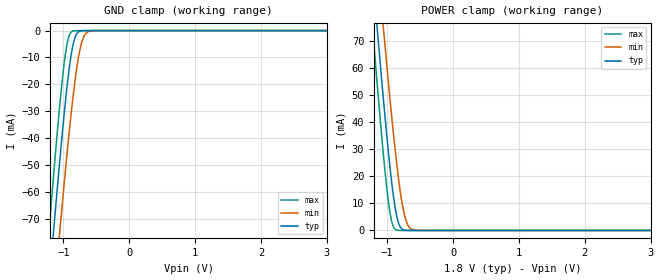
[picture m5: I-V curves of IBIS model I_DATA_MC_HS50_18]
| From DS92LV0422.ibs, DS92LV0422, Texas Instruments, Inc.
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|   I_DATA_MC_HS50_18
[Model]   I_DATA_MC_HS50_18
Model_type   Input
Vinl = 0.63V
Vinh = 1.17V
|   typ   min   max
|   (nom)   (weak)   (fast)
C_comp   0.5928pF   0.5928pF   0.5928pF
[Voltage Range]   1.800V   1.710V   1.890V
[Temperature Range]   25.0   105.0   -40.0
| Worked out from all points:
|   GND clamp passes 1 mA (typ) near -0.79 V on its own axis
|   POWER clamp passes 1 mA (typ) near -0.79 V on its own axis
[GND Clamp]
|   Voltage   I(typ)   I(min)   I(max)
-1.8V     -271mA     -291mA     -255.6mA
-1.228V   -97.13mA   -122.7mA   -76.8mA
-1.201V   -89.24mA   -115mA     -68.74mA
-1.147V   -73.66mA   -99.76mA   -52.9mA
-1.055V   -48.09mA   -74.42mA   -27.54mA
-957.6mV  -23.57mA   -48.85mA   -6.691mA
-871.2mV  -7.355mA   -28.24mA   -349uA
-811.8mV  -1.796mA   -16.31mA   -35.11uA
-741.6mV  -166.7uA   -6.23mA    -13.16uA
-682.2mV  -22.73uA   -1.842mA   -9.797uA
-601.2mV  -4.882uA   -201.7uA   -6.456uA
3.595V    0A         0A         0A
[POWER Clamp]
|   Voltage   I(typ)   I(min)   I(max)
-1.8V     270.2mA    290.2mA    254.9mA
-1.228V   96.77mA    122.3mA    76.49mA
-1.201V   88.91mA    114.6mA    68.45mA
-1.147V   73.37mA    99.4mA     52.66mA
-1.055V   47.86mA    74.12mA    27.37mA
-957.6mV  23.41mA    48.61mA    6.602mA
-871.2mV  7.263mA    28.06mA    324uA
-811.8mV  1.758mA    16.17mA    18.49uA
-741.6mV  155.5uA    6.146mA    576.2nA
-682.2mV  16.1uA     1.807mA    26.76nA
-601.2mV  704.2nA    194.6uA    0A
3.595V    0A         0A         0A
